VERSION 5.7 ;
  NOWIREEXTENSIONATPIN ON ;
  DIVIDERCHAR "/" ;
  BUSBITCHARS "[]" ;
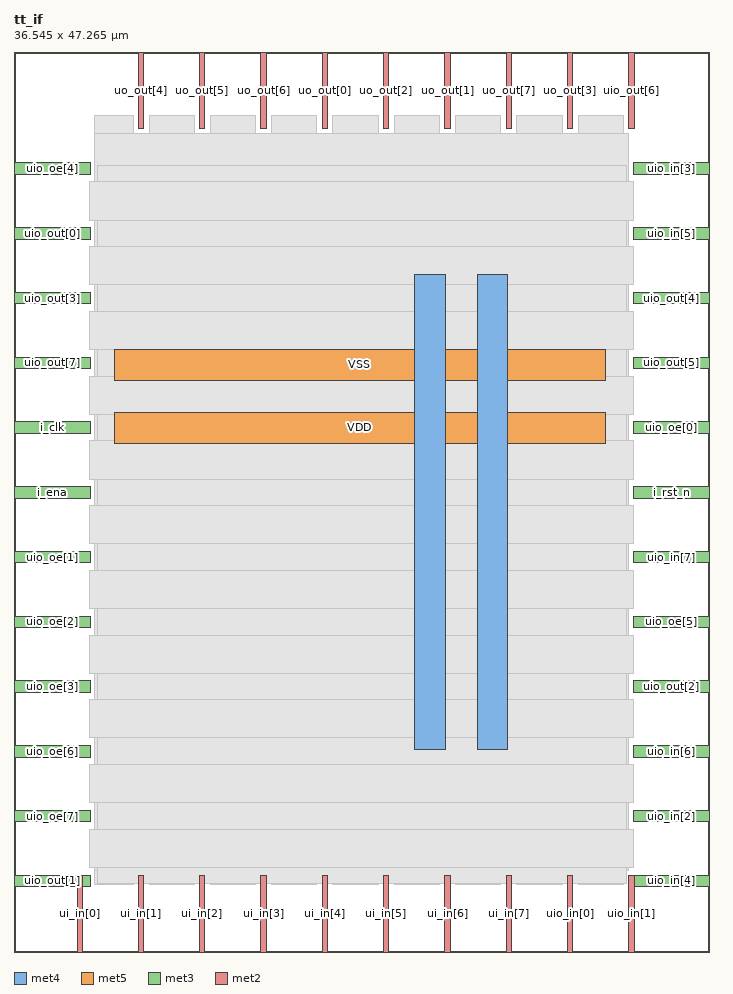
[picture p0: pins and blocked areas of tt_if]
MACRO tt_if
  CLASS BLOCK ;
  FOREIGN tt_if ;
  ORIGIN 0.000 0.000 ;
  SIZE 36.545 BY 47.265 ;
  PIN VDD
    DIRECTION INOUT ;
    USE POWER ;
    PORT
      LAYER met4 ;
        RECT 21.040 10.640 22.640 35.600 ;
    END
    PORT
      LAYER met5 ;
        RECT 5.280 26.730 31.060 28.330 ;
    END
  END VDD
  PIN VSS
    DIRECTION INOUT ;
    USE GROUND ;
    PORT
      LAYER met4 ;
        RECT 24.340 10.640 25.940 35.600 ;
    END
    PORT
      LAYER met5 ;
        RECT 5.280 30.030 31.060 31.630 ;
    END
  END VSS
  PIN i_clk
    DIRECTION INPUT ;
    USE SIGNAL ;
    ANTENNAGATEAREA 0.852000 ;
    PORT
      LAYER met3 ;
        RECT 0.000 27.240 4.000 27.840 ;
    END
  END i_clk
  PIN i_ena
    DIRECTION INPUT ;
    USE SIGNAL ;
    ANTENNAGATEAREA 0.126000 ;
    PORT
      LAYER met3 ;
        RECT 0.000 23.840 4.000 24.440 ;
    END
  END i_ena
  PIN i_rst_n
    DIRECTION INPUT ;
    USE SIGNAL ;
    ANTENNAGATEAREA 0.126000 ;
    PORT
      LAYER met3 ;
        RECT 32.545 23.840 36.545 24.440 ;
    END
  END i_rst_n
  PIN ui_in[0]
    DIRECTION INPUT ;
    USE SIGNAL ;
    PORT
      LAYER met2 ;
        RECT 3.310 0.000 3.590 4.000 ;
    END
  END ui_in[0]
  PIN ui_in[1]
    DIRECTION INPUT ;
    USE SIGNAL ;
    PORT
      LAYER met2 ;
        RECT 6.530 0.000 6.810 4.000 ;
    END
  END ui_in[1]
  PIN ui_in[2]
    DIRECTION INPUT ;
    USE SIGNAL ;
    PORT
      LAYER met2 ;
        RECT 9.750 0.000 10.030 4.000 ;
    END
  END ui_in[2]
  PIN ui_in[3]
    DIRECTION INPUT ;
    USE SIGNAL ;
    PORT
      LAYER met2 ;
        RECT 12.970 0.000 13.250 4.000 ;
    END
  END ui_in[3]
  PIN ui_in[4]
    DIRECTION INPUT ;
    USE SIGNAL ;
    PORT
      LAYER met2 ;
        RECT 16.190 0.000 16.470 4.000 ;
    END
  END ui_in[4]
  PIN ui_in[5]
    DIRECTION INPUT ;
    USE SIGNAL ;
    PORT
      LAYER met2 ;
        RECT 19.410 0.000 19.690 4.000 ;
    END
  END ui_in[5]
  PIN ui_in[6]
    DIRECTION INPUT ;
    USE SIGNAL ;
    PORT
      LAYER met2 ;
        RECT 22.630 0.000 22.910 4.000 ;
    END
  END ui_in[6]
  PIN ui_in[7]
    DIRECTION INPUT ;
    USE SIGNAL ;
    PORT
      LAYER met2 ;
        RECT 25.850 0.000 26.130 4.000 ;
    END
  END ui_in[7]
  PIN uio_in[0]
    DIRECTION INPUT ;
    USE SIGNAL ;
    PORT
      LAYER met2 ;
        RECT 29.070 0.000 29.350 4.000 ;
    END
  END uio_in[0]
  PIN uio_in[1]
    DIRECTION INPUT ;
    USE SIGNAL ;
    PORT
      LAYER met2 ;
        RECT 32.290 0.000 32.570 4.000 ;
    END
  END uio_in[1]
  PIN uio_in[2]
    DIRECTION INPUT ;
    USE SIGNAL ;
    PORT
      LAYER met3 ;
        RECT 32.545 6.840 36.545 7.440 ;
    END
  END uio_in[2]
  PIN uio_in[3]
    DIRECTION INPUT ;
    USE SIGNAL ;
    PORT
      LAYER met3 ;
        RECT 32.545 40.840 36.545 41.440 ;
    END
  END uio_in[3]
  PIN uio_in[4]
    DIRECTION INPUT ;
    USE SIGNAL ;
    PORT
      LAYER met3 ;
        RECT 32.545 3.440 36.545 4.040 ;
    END
  END uio_in[4]
  PIN uio_in[5]
    DIRECTION INPUT ;
    USE SIGNAL ;
    PORT
      LAYER met3 ;
        RECT 32.545 37.440 36.545 38.040 ;
    END
  END uio_in[5]
  PIN uio_in[6]
    DIRECTION INPUT ;
    USE SIGNAL ;
    PORT
      LAYER met3 ;
        RECT 32.545 10.240 36.545 10.840 ;
    END
  END uio_in[6]
  PIN uio_in[7]
    DIRECTION INPUT ;
    USE SIGNAL ;
    PORT
      LAYER met3 ;
        RECT 32.545 20.440 36.545 21.040 ;
    END
  END uio_in[7]
  PIN uio_oe[0]
    DIRECTION OUTPUT ;
    USE SIGNAL ;
    PORT
      LAYER met3 ;
        RECT 32.545 27.240 36.545 27.840 ;
    END
  END uio_oe[0]
  PIN uio_oe[1]
    DIRECTION OUTPUT ;
    USE SIGNAL ;
    PORT
      LAYER met3 ;
        RECT 0.000 20.440 4.000 21.040 ;
    END
  END uio_oe[1]
  PIN uio_oe[2]
    DIRECTION OUTPUT ;
    USE SIGNAL ;
    PORT
      LAYER met3 ;
        RECT 0.000 17.040 4.000 17.640 ;
    END
  END uio_oe[2]
  PIN uio_oe[3]
    DIRECTION OUTPUT ;
    USE SIGNAL ;
    PORT
      LAYER met3 ;
        RECT 0.000 13.640 4.000 14.240 ;
    END
  END uio_oe[3]
  PIN uio_oe[4]
    DIRECTION OUTPUT ;
    USE SIGNAL ;
    PORT
      LAYER met3 ;
        RECT 0.000 40.840 4.000 41.440 ;
    END
  END uio_oe[4]
  PIN uio_oe[5]
    DIRECTION OUTPUT ;
    USE SIGNAL ;
    PORT
      LAYER met3 ;
        RECT 32.545 17.040 36.545 17.640 ;
    END
  END uio_oe[5]
  PIN uio_oe[6]
    DIRECTION OUTPUT ;
    USE SIGNAL ;
    PORT
      LAYER met3 ;
        RECT 0.000 10.240 4.000 10.840 ;
    END
  END uio_oe[6]
  PIN uio_oe[7]
    DIRECTION OUTPUT ;
    USE SIGNAL ;
    PORT
      LAYER met3 ;
        RECT 0.000 6.840 4.000 7.440 ;
    END
  END uio_oe[7]
  PIN uio_out[0]
    DIRECTION OUTPUT ;
    USE SIGNAL ;
    PORT
      LAYER met3 ;
        RECT 0.000 37.440 4.000 38.040 ;
    END
  END uio_out[0]
  PIN uio_out[1]
    DIRECTION OUTPUT ;
    USE SIGNAL ;
    PORT
      LAYER met3 ;
        RECT 0.000 3.440 4.000 4.040 ;
    END
  END uio_out[1]
  PIN uio_out[2]
    DIRECTION OUTPUT ;
    USE SIGNAL ;
    PORT
      LAYER met3 ;
        RECT 32.545 13.640 36.545 14.240 ;
    END
  END uio_out[2]
  PIN uio_out[3]
    DIRECTION OUTPUT ;
    USE SIGNAL ;
    PORT
      LAYER met3 ;
        RECT 0.000 34.040 4.000 34.640 ;
    END
  END uio_out[3]
  PIN uio_out[4]
    DIRECTION OUTPUT ;
    USE SIGNAL ;
    PORT
      LAYER met3 ;
        RECT 32.545 34.040 36.545 34.640 ;
    END
  END uio_out[4]
  PIN uio_out[5]
    DIRECTION OUTPUT ;
    USE SIGNAL ;
    PORT
      LAYER met3 ;
        RECT 32.545 30.640 36.545 31.240 ;
    END
  END uio_out[5]
  PIN uio_out[6]
    DIRECTION OUTPUT ;
    USE SIGNAL ;
    PORT
      LAYER met2 ;
        RECT 32.290 43.265 32.570 47.265 ;
    END
  END uio_out[6]
  PIN uio_out[7]
    DIRECTION OUTPUT ;
    USE SIGNAL ;
    PORT
      LAYER met3 ;
        RECT 0.000 30.640 4.000 31.240 ;
    END
  END uio_out[7]
  PIN uo_out[0]
    DIRECTION OUTPUT ;
    USE SIGNAL ;
    ANTENNADIFFAREA 0.445500 ;
    PORT
      LAYER met2 ;
        RECT 16.190 43.265 16.470 47.265 ;
    END
  END uo_out[0]
  PIN uo_out[1]
    DIRECTION OUTPUT ;
    USE SIGNAL ;
    ANTENNADIFFAREA 0.445500 ;
    PORT
      LAYER met2 ;
        RECT 22.630 43.265 22.910 47.265 ;
    END
  END uo_out[1]
  PIN uo_out[2]
    DIRECTION OUTPUT ;
    USE SIGNAL ;
    ANTENNADIFFAREA 0.445500 ;
    PORT
      LAYER met2 ;
        RECT 19.410 43.265 19.690 47.265 ;
    END
  END uo_out[2]
  PIN uo_out[3]
    DIRECTION OUTPUT ;
    USE SIGNAL ;
    ANTENNADIFFAREA 0.445500 ;
    PORT
      LAYER met2 ;
        RECT 29.070 43.265 29.350 47.265 ;
    END
  END uo_out[3]
  PIN uo_out[4]
    DIRECTION OUTPUT ;
    USE SIGNAL ;
    PORT
      LAYER met2 ;
        RECT 6.530 43.265 6.810 47.265 ;
    END
  END uo_out[4]
  PIN uo_out[5]
    DIRECTION OUTPUT ;
    USE SIGNAL ;
    PORT
      LAYER met2 ;
        RECT 9.750 43.265 10.030 47.265 ;
    END
  END uo_out[5]
  PIN uo_out[6]
    DIRECTION OUTPUT ;
    USE SIGNAL ;
    PORT
      LAYER met2 ;
        RECT 12.970 43.265 13.250 47.265 ;
    END
  END uo_out[6]
  PIN uo_out[7]
    DIRECTION OUTPUT ;
    USE SIGNAL ;
    PORT
      LAYER met2 ;
        RECT 25.850 43.265 26.130 47.265 ;
    END
  END uo_out[7]
  OBS
      LAYER nwell ;
        RECT 5.330 10.795 31.010 35.550 ;
      LAYER li1 ;
        RECT 5.520 10.795 30.820 35.445 ;
      LAYER met1 ;
        RECT 4.210 10.640 30.820 35.600 ;
      LAYER met2 ;
        RECT 4.230 42.985 6.250 43.930 ;
        RECT 7.090 42.985 9.470 43.930 ;
        RECT 10.310 42.985 12.690 43.930 ;
        RECT 13.530 42.985 15.910 43.930 ;
        RECT 16.750 42.985 19.130 43.930 ;
        RECT 19.970 42.985 22.350 43.930 ;
        RECT 23.190 42.985 25.570 43.930 ;
        RECT 26.410 42.985 28.790 43.930 ;
        RECT 29.630 42.985 32.010 43.930 ;
        RECT 4.230 4.280 32.290 42.985 ;
        RECT 4.230 3.555 6.250 4.280 ;
        RECT 7.090 3.555 9.470 4.280 ;
        RECT 10.310 3.555 12.690 4.280 ;
        RECT 13.530 3.555 15.910 4.280 ;
        RECT 16.750 3.555 19.130 4.280 ;
        RECT 19.970 3.555 22.350 4.280 ;
        RECT 23.190 3.555 25.570 4.280 ;
        RECT 26.410 3.555 28.790 4.280 ;
        RECT 29.630 3.555 32.010 4.280 ;
      LAYER met3 ;
        RECT 4.400 40.440 32.145 41.305 ;
        RECT 3.990 38.440 32.545 40.440 ;
        RECT 4.400 37.040 32.145 38.440 ;
        RECT 3.990 35.040 32.545 37.040 ;
        RECT 4.400 33.640 32.145 35.040 ;
        RECT 3.990 31.640 32.545 33.640 ;
        RECT 4.400 30.240 32.145 31.640 ;
        RECT 3.990 28.240 32.545 30.240 ;
        RECT 4.400 26.840 32.145 28.240 ;
        RECT 3.990 24.840 32.545 26.840 ;
        RECT 4.400 23.440 32.145 24.840 ;
        RECT 3.990 21.440 32.545 23.440 ;
        RECT 4.400 20.040 32.145 21.440 ;
        RECT 3.990 18.040 32.545 20.040 ;
        RECT 4.400 16.640 32.145 18.040 ;
        RECT 3.990 14.640 32.545 16.640 ;
        RECT 4.400 13.240 32.145 14.640 ;
        RECT 3.990 11.240 32.545 13.240 ;
        RECT 4.400 9.840 32.145 11.240 ;
        RECT 3.990 7.840 32.545 9.840 ;
        RECT 4.400 6.440 32.145 7.840 ;
        RECT 3.990 4.440 32.545 6.440 ;
        RECT 4.400 3.575 32.145 4.440 ;
  END
END tt_if
END LIBRARY

